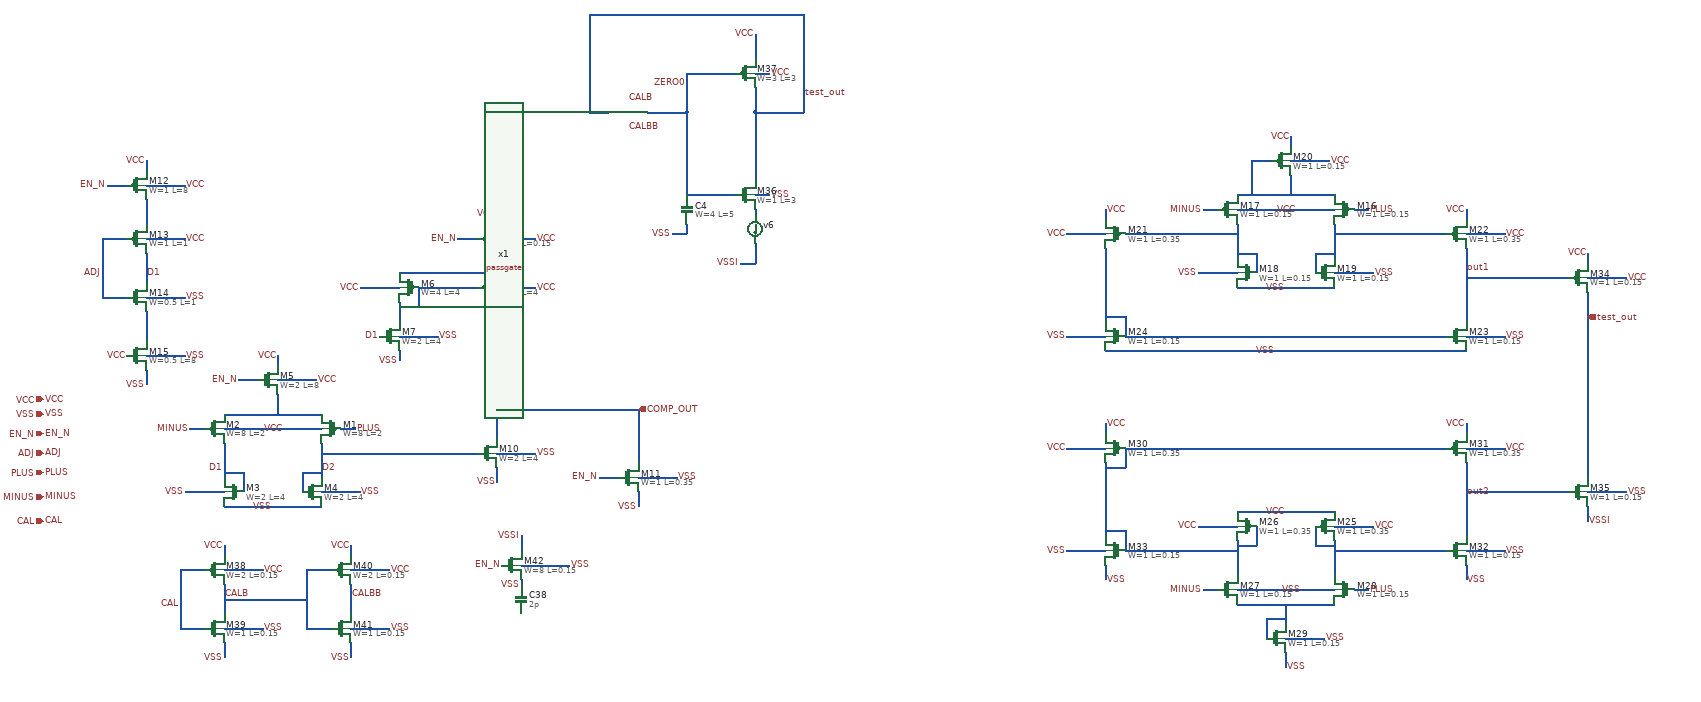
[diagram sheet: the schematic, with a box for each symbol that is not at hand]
v {xschem version=3.4.5 file_version=1.2
}
G {}
K {}
V {}
S {}
E {}
N 230 -90 230 -20 {
lab=D1}
N 430 -90 430 -20 {
lab=D2}
N 390 -30 390 10 {
lab=D2}
N 390 -30 430 -30 {
lab=D2}
N 270 -30 270 10 {
lab=D1}
N 230 -30 270 -30 {
lab=D1}
N 230 40 430 40 {
lab=VSS}
N 230 -150 430 -150 {
lab=#net1}
N 340 -190 340 -150 {
lab=#net1}
N 470 -120 500 -120 {
lab=PLUS}
N 160 -120 190 -120 {
lab=MINUS}
N 260 -220 300 -220 {
lab=EN_N}
N 590 -380 590 -340 {
lab=#net2}
N 340 -270 340 -250 {
lab=VCC}
N 340 -220 420 -220 {
lab=VCC}
N 230 -120 310 -120 {
lab=VCC}
N 310 -120 430 -120 {
lab=VCC}
N 430 10 510 10 {
lab=VSS}
N 150 10 230 10 {
lab=VSS}
N 590 -310 670 -310 {
lab=VSS}
N 630 -410 630 -370 {
lab=#net2}
N 590 -370 630 -370 {
lab=#net2}
N 630 -410 750 -410 {
lab=#net2}
N 790 -410 870 -410 {
lab=VCC}
N 510 -410 590 -410 {
lab=VCC}
N 590 -440 790 -440 {
lab=#net3}
N 790 -480 790 -440 {
lab=#net3}
N 710 -510 750 -510 {
lab=EN_N}
N 790 -510 870 -510 {
lab=VCC}
N 790 -560 790 -540 {
lab=VCC}
N 790 -380 790 -100 {
lab=COMP_OUT}
N 430 -70 750 -70 {
lab=D2}
N 790 -70 870 -70 {
lab=VSS}
N 790 -40 790 -10 {
lab=VSS}
N 1080 10 1080 40 {
lab=VSS}
N 1000 -20 1040 -20 {
lab=EN_N}
N 1080 -160 1080 -50 {
lab=COMP_OUT}
N 790 -160 1080 -160 {
lab=COMP_OUT}
N 70 -360 70 -300 {
lab=#net4}
N 70 -480 70 -420 {
lab=D1}
N 70 -590 70 -540 {
lab=#net5}
N 70 -670 70 -650 {
lab=VCC}
N -20 -510 30 -510 {
lab=ADJ}
N -20 -390 30 -390 {
lab=ADJ}
N -20 -510 -20 -390 {
lab=ADJ}
N 70 -240 70 -210 {
lab=VSS}
N 70 -510 150 -510 {
lab=VCC}
N 70 -620 150 -620 {
lab=VCC}
N 70 -270 150 -270 {
lab=VSS}
N 70 -390 150 -390 {
lab=VSS}
N -10 -620 30 -620 {
lab=EN_N}
N 2310 -540 2310 -470 {
lab=#net6}
N 2510 -540 2510 -470 {
lab=#net7}
N 2470 -480 2470 -440 {
lab=#net7}
N 2470 -480 2510 -480 {
lab=#net7}
N 2350 -480 2350 -440 {
lab=#net6}
N 2310 -480 2350 -480 {
lab=#net6}
N 2310 -410 2510 -410 {
lab=VSS}
N 2310 -600 2510 -600 {
lab=#net8}
N 2420 -640 2420 -600 {
lab=#net8}
N 2550 -570 2580 -570 {
lab=PLUS}
N 2240 -570 2270 -570 {
lab=MINUS}
N 2340 -670 2380 -670 {
lab=#net8}
N 2420 -720 2420 -700 {
lab=VCC}
N 2420 -670 2500 -670 {
lab=VCC}
N 2310 -570 2390 -570 {
lab=VCC}
N 2390 -570 2510 -570 {
lab=VCC}
N 2510 -440 2590 -440 {
lab=VSS}
N 2230 -440 2310 -440 {
lab=VSS}
N 2040 -490 2040 -340 {
lab=#net9}
N 2040 -570 2040 -550 {
lab=VCC}
N 1960 -520 2040 -520 {
lab=VCC}
N 2080 -520 2310 -520 {
lab=#net6}
N 2780 -570 2780 -550 {
lab=VCC}
N 2780 -520 2860 -520 {
lab=VCC}
N 2510 -520 2740 -520 {
lab=#net7}
N 2240 -280 2780 -280 {
lab=VSS}
N 2780 -310 2860 -310 {
lab=VSS}
N 2780 -490 2780 -340 {
lab=out1}
N 2040 -280 2240 -280 {
lab=VSS}
N 1960 -310 2040 -310 {
lab=VSS}
N 2080 -310 2740 -310 {
lab=#net9}
N 590 -280 590 -260 {
lab=VSS}
N 1080 -20 1160 -20 {
lab=VSS}
N 2080 -350 2080 -310 {
lab=#net9}
N 2040 -350 2080 -350 {
lab=#net9}
N 2340 -670 2340 -600 {
lab=#net8}
N 2310 110 2310 180 {
lab=#net10}
N 2510 110 2510 180 {
lab=#net11}
N 2310 240 2510 240 {
lab=#net12}
N 2550 210 2580 210 {
lab=PLUS}
N 2240 210 2270 210 {
lab=MINUS}
N 2040 -50 2040 100 {
lab=#net10}
N 2040 -130 2040 -110 {
lab=VCC}
N 1960 -80 2040 -80 {
lab=VCC}
N 2080 130 2310 130 {
lab=#net10}
N 2780 -130 2780 -110 {
lab=VCC}
N 2780 -80 2860 -80 {
lab=VCC}
N 2510 130 2740 130 {
lab=#net11}
N 2780 130 2860 130 {
lab=VSS}
N 2780 -50 2780 100 {
lab=out2}
N 1960 130 2040 130 {
lab=VSS}
N 2080 90 2080 130 {
lab=#net10}
N 2040 90 2080 90 {
lab=#net10}
N 2080 -80 2080 -40 {
lab=#net10}
N 2040 -40 2080 -40 {
lab=#net10}
N 2410 240 2410 280 {
lab=#net12}
N 2370 270 2370 310 {
lab=#net12}
N 2370 270 2410 270 {
lab=#net12}
N 2470 80 2470 120 {
lab=#net11}
N 2470 120 2510 120 {
lab=#net11}
N 2350 80 2350 120 {
lab=#net10}
N 2310 120 2350 120 {
lab=#net10}
N 2310 50 2510 50 {
lab=VCC}
N 2410 340 2410 370 {
lab=VSS}
N 2410 310 2490 310 {
lab=VSS}
N 2310 210 2510 210 {
lab=VSS}
N 2510 80 2590 80 {
lab=VCC}
N 2230 80 2310 80 {
lab=VCC}
N 2040 160 2040 190 {
lab=VSS}
N 2780 160 2780 190 {
lab=VSS}
N 2080 -80 2740 -80 {
lab=#net10}
N 3030 -480 3030 -460 {
lab=VCC}
N 3030 -430 3110 -430 {
lab=VCC}
N 2780 -430 2990 -430 {
lab=out1}
N 3030 -400 3030 -330 {
lab=test_out}
N 3030 10 3110 10 {
lab=VSS}
N 3030 40 3030 70 {
lab=VSS}
N 3030 -330 3030 -20 {
lab=test_out}
N 2780 10 2990 10 {
lab=out2}
N 1320 -600 1350 -600 {lab=VSS}
N 1320 -850 1350 -850 {lab=VCC}
N 1320 -930 1320 -880 {lab=VCC}
N 1290 -460 1320 -460 {lab=VSSI}
N 1320 -500 1320 -460 {lab=VSSI}
N 1180 -600 1280 -600 {lab=ZERO0}
N 1180 -770 1180 -600 {lab=ZERO0}
N 1100 -770 1180 -770 {lab=ZERO0}
N 980 -770 1020 -770 {lab=test_out}
N 980 -970 980 -770 {lab=test_out}
N 980 -970 1420 -970 {lab=test_out}
N 1320 -770 1420 -770 {lab=test_out}
N 1420 -970 1420 -770 {lab=test_out}
N 1320 -820 1320 -770 {lab=test_out}
N 1180 -850 1180 -770 {lab=ZERO0}
N 1320 -770 1320 -630 {lab=test_out}
N 1180 -850 1280 -850 {lab=ZERO0}
N 1150 -520 1180 -520 {lab=VSS}
N 1180 -540 1180 -520 { lab=VSS}
N 1320 -570 1320 -560 { lab=#net13}
N 230 200 230 260 {
lab=CALB}
N 140 170 190 170 {
lab=CAL}
N 140 290 190 290 {
lab=CAL}
N 140 170 140 290 {
lab=CAL}
N 230 170 310 170 {
lab=VCC}
N 230 290 310 290 {
lab=VSS}
N 230 320 230 350 {
lab=VSS}
N 490 200 490 260 {
lab=CALBB}
N 400 170 450 170 {
lab=CALB}
N 400 290 450 290 {
lab=CALB}
N 400 170 400 290 {
lab=CALB}
N 490 170 570 170 {
lab=VCC}
N 490 290 570 290 {
lab=VSS}
N 490 320 490 350 {
lab=VSS}
N 230 230 400 230 {
lab=CALB}
N 230 120 230 140 {
lab=VCC}
N 490 120 490 140 {
lab=VCC}
N 840 160 940 160 {lab=VSS}
N 840 100 840 130 {lab=VSSI}
N 840 190 840 220 {lab=VSS}
C {sky130_fd_pr/pfet_01v8.sym} 450 -120 0 1 {name=M1
L=2
W=8
nf=1
mult=1
ad="'int((nf+1)/2) * W/nf * 0.29'" 
pd="'2*int((nf+1)/2) * (W/nf + 0.29)'"
as="'int((nf+2)/2) * W/nf * 0.29'" 
ps="'2*int((nf+2)/2) * (W/nf + 0.29)'"
nrd="'0.29 / W'" nrs="'0.29 / W'"
sa=0 sb=0 sd=0
model=pfet_01v8
spiceprefix=X
}
C {sky130_fd_pr/pfet_01v8.sym} 210 -120 0 0 {name=M2
L=2
W=8
nf=1
mult=1
ad="'int((nf+1)/2) * W/nf * 0.29'" 
pd="'2*int((nf+1)/2) * (W/nf + 0.29)'"
as="'int((nf+2)/2) * W/nf * 0.29'" 
ps="'2*int((nf+2)/2) * (W/nf + 0.29)'"
nrd="'0.29 / W'" nrs="'0.29 / W'"
sa=0 sb=0 sd=0
model=pfet_01v8
spiceprefix=X
}
C {sky130_fd_pr/nfet_01v8_lvt.sym} 250 10 0 1 {name=M3
L=4
W=2
nf=1
mult=1
ad="'int((nf+1)/2) * W/nf * 0.29'" 
pd="'2*int((nf+1)/2) * (W/nf + 0.29)'"
as="'int((nf+2)/2) * W/nf * 0.29'" 
ps="'2*int((nf+2)/2) * (W/nf + 0.29)'"
nrd="'0.29 / W'" nrs="'0.29 / W'"
sa=0 sb=0 sd=0
model=nfet_01v8_lvt
spiceprefix=X
}
C {sky130_fd_pr/nfet_01v8_lvt.sym} 410 10 0 0 {name=M4
L=4
W=2
nf=1
mult=1
ad="'int((nf+1)/2) * W/nf * 0.29'" 
pd="'2*int((nf+1)/2) * (W/nf + 0.29)'"
as="'int((nf+2)/2) * W/nf * 0.29'" 
ps="'2*int((nf+2)/2) * (W/nf + 0.29)'"
nrd="'0.29 / W'" nrs="'0.29 / W'"
sa=0 sb=0 sd=0
model=nfet_01v8_lvt
spiceprefix=X
}
C {sky130_fd_pr/pfet_01v8.sym} 320 -220 0 0 {name=M5
L=8
W=2
nf=1
mult=1
ad="'int((nf+1)/2) * W/nf * 0.29'" 
pd="'2*int((nf+1)/2) * (W/nf + 0.29)'"
as="'int((nf+2)/2) * W/nf * 0.29'" 
ps="'2*int((nf+2)/2) * (W/nf + 0.29)'"
nrd="'0.29 / W'" nrs="'0.29 / W'"
sa=0 sb=0 sd=0
model=pfet_01v8
spiceprefix=X
}
C {sky130_fd_pr/pfet_01v8_lvt.sym} 610 -410 0 1 {name=M6
L=4
W=4
nf=1
mult=1
ad="'int((nf+1)/2) * W/nf * 0.29'" 
pd="'2*int((nf+1)/2) * (W/nf + 0.29)'"
as="'int((nf+2)/2) * W/nf * 0.29'" 
ps="'2*int((nf+2)/2) * (W/nf + 0.29)'"
nrd="'0.29 / W'" nrs="'0.29 / W'"
sa=0 sb=0 sd=0
model=pfet_01v8_lvt
spiceprefix=X
}
C {sky130_fd_pr/nfet_01v8_lvt.sym} 570 -310 0 0 {name=M7
L=4
W=2
nf=1
mult=1
ad="'int((nf+1)/2) * W/nf * 0.29'" 
pd="'2*int((nf+1)/2) * (W/nf + 0.29)'"
as="'int((nf+2)/2) * W/nf * 0.29'" 
ps="'2*int((nf+2)/2) * (W/nf + 0.29)'"
nrd="'0.29 / W'" nrs="'0.29 / W'"
sa=0 sb=0 sd=0
model=nfet_01v8_lvt
spiceprefix=X
}
C {devices/lab_wire.sym} 230 -40 0 0 {name=p1 sig_type=std_logic lab=D1}
C {devices/lab_wire.sym} 430 -40 0 1 {name=p2 sig_type=std_logic lab=D2}
C {devices/lab_wire.sym} 500 -120 0 1 {name=p3 sig_type=std_logic lab=PLUS}
C {devices/lab_wire.sym} 160 -120 0 0 {name=p4 sig_type=std_logic lab=MINUS}
C {devices/lab_wire.sym} 260 -220 0 0 {name=p5 sig_type=std_logic lab=EN_N}
C {devices/lab_wire.sym} 340 -270 0 0 {name=p6 sig_type=std_logic lab=VCC}
C {devices/lab_wire.sym} 420 -220 0 1 {name=p7 sig_type=std_logic lab=VCC}
C {devices/lab_wire.sym} 310 -120 0 1 {name=p8 sig_type=std_logic lab=VCC}
C {devices/lab_wire.sym} 510 10 0 1 {name=p9 sig_type=std_logic lab=VSS}
C {devices/lab_wire.sym} 150 10 0 0 {name=p10 sig_type=std_logic lab=VSS}
C {devices/lab_wire.sym} 670 -310 0 1 {name=p11 sig_type=std_logic lab=VSS}
C {devices/lab_wire.sym} 550 -310 0 0 {name=p12 sig_type=std_logic lab=D1}
C {sky130_fd_pr/pfet_01v8_lvt.sym} 770 -410 0 0 {name=M8
L=4
W=4
nf=1
mult=1
ad="'int((nf+1)/2) * W/nf * 0.29'" 
pd="'2*int((nf+1)/2) * (W/nf + 0.29)'"
as="'int((nf+2)/2) * W/nf * 0.29'" 
ps="'2*int((nf+2)/2) * (W/nf + 0.29)'"
nrd="'0.29 / W'" nrs="'0.29 / W'"
sa=0 sb=0 sd=0
model=pfet_01v8_lvt
spiceprefix=X
}
C {devices/lab_wire.sym} 870 -410 0 1 {name=p13 sig_type=std_logic lab=VCC}
C {devices/lab_wire.sym} 510 -410 0 0 {name=p14 sig_type=std_logic lab=VCC}
C {sky130_fd_pr/pfet_01v8.sym} 770 -510 0 0 {name=M9
L=0.15
W=5
nf=1
mult=1
ad="'int((nf+1)/2) * W/nf * 0.29'" 
pd="'2*int((nf+1)/2) * (W/nf + 0.29)'"
as="'int((nf+2)/2) * W/nf * 0.29'" 
ps="'2*int((nf+2)/2) * (W/nf + 0.29)'"
nrd="'0.29 / W'" nrs="'0.29 / W'"
sa=0 sb=0 sd=0
model=pfet_01v8
spiceprefix=X
}
C {devices/lab_wire.sym} 710 -510 0 0 {name=p15 sig_type=std_logic lab=EN_N}
C {devices/lab_wire.sym} 870 -510 0 1 {name=p16 sig_type=std_logic lab=VCC}
C {devices/lab_wire.sym} 790 -560 0 0 {name=p17 sig_type=std_logic lab=VCC}
C {devices/lab_wire.sym} 330 40 0 0 {name=p18 sig_type=std_logic lab=VSS}
C {sky130_fd_pr/nfet_01v8_lvt.sym} 770 -70 0 0 {name=M10
L=4
W=2
nf=1
mult=1
ad="'int((nf+1)/2) * W/nf * 0.29'" 
pd="'2*int((nf+1)/2) * (W/nf + 0.29)'"
as="'int((nf+2)/2) * W/nf * 0.29'" 
ps="'2*int((nf+2)/2) * (W/nf + 0.29)'"
nrd="'0.29 / W'" nrs="'0.29 / W'"
sa=0 sb=0 sd=0
model=nfet_01v8_lvt
spiceprefix=X
}
C {devices/lab_wire.sym} 870 -70 0 1 {name=p19 sig_type=std_logic lab=VSS}
C {devices/lab_wire.sym} 790 -10 0 0 {name=p20 sig_type=std_logic lab=VSS}
C {sky130_fd_pr/nfet_01v8.sym} 1060 -20 0 0 {name=M11
L=0.35
W=1
nf=1
mult=1
ad="'int((nf+1)/2) * W/nf * 0.29'" 
pd="'2*int((nf+1)/2) * (W/nf + 0.29)'"
as="'int((nf+2)/2) * W/nf * 0.29'" 
ps="'2*int((nf+2)/2) * (W/nf + 0.29)'"
nrd="'0.29 / W'" nrs="'0.29 / W'"
sa=0 sb=0 sd=0
model=nfet_01v8
spiceprefix=X
}
C {devices/lab_wire.sym} 1080 40 0 0 {name=p21 sig_type=std_logic lab=VSS}
C {devices/lab_wire.sym} 1000 -20 0 0 {name=p22 sig_type=std_logic lab=EN_N}
C {sky130_fd_pr/pfet_01v8.sym} 50 -620 0 0 {name=M12
L=8
W=1
nf=1
mult=1
ad="'int((nf+1)/2) * W/nf * 0.29'" 
pd="'2*int((nf+1)/2) * (W/nf + 0.29)'"
as="'int((nf+2)/2) * W/nf * 0.29'" 
ps="'2*int((nf+2)/2) * (W/nf + 0.29)'"
nrd="'0.29 / W'" nrs="'0.29 / W'"
sa=0 sb=0 sd=0
model=pfet_01v8
spiceprefix=X
}
C {sky130_fd_pr/pfet_01v8_lvt.sym} 50 -510 0 0 {name=M13
L=1
W=1
nf=1
mult=1
ad="'int((nf+1)/2) * W/nf * 0.29'" 
pd="'2*int((nf+1)/2) * (W/nf + 0.29)'"
as="'int((nf+2)/2) * W/nf * 0.29'" 
ps="'2*int((nf+2)/2) * (W/nf + 0.29)'"
nrd="'0.29 / W'" nrs="'0.29 / W'"
sa=0 sb=0 sd=0
model=pfet_01v8_lvt
spiceprefix=X
}
C {sky130_fd_pr/nfet_01v8_lvt.sym} 50 -390 0 0 {name=M14
L=1
W=0.5
nf=1
mult=1
ad="'int((nf+1)/2) * W/nf * 0.29'" 
pd="'2*int((nf+1)/2) * (W/nf + 0.29)'"
as="'int((nf+2)/2) * W/nf * 0.29'" 
ps="'2*int((nf+2)/2) * (W/nf + 0.29)'"
nrd="'0.29 / W'" nrs="'0.29 / W'"
sa=0 sb=0 sd=0
model=nfet_01v8_lvt
spiceprefix=X
}
C {sky130_fd_pr/nfet_01v8_lvt.sym} 50 -270 0 0 {name=M15
L=8
W=0.5
nf=1
mult=1
ad="'int((nf+1)/2) * W/nf * 0.29'" 
pd="'2*int((nf+1)/2) * (W/nf + 0.29)'"
as="'int((nf+2)/2) * W/nf * 0.29'" 
ps="'2*int((nf+2)/2) * (W/nf + 0.29)'"
nrd="'0.29 / W'" nrs="'0.29 / W'"
sa=0 sb=0 sd=0
model=nfet_01v8_lvt
spiceprefix=X
}
C {devices/lab_wire.sym} 70 -670 0 0 {name=p23 sig_type=std_logic lab=VCC}
C {devices/lab_wire.sym} 70 -440 0 1 {name=p24 sig_type=std_logic lab=D1}
C {devices/lab_wire.sym} -20 -440 0 0 {name=p25 sig_type=std_logic lab=ADJ}
C {devices/lab_wire.sym} 70 -210 0 0 {name=p26 sig_type=std_logic lab=VSS}
C {devices/lab_wire.sym} 150 -510 0 1 {name=p27 sig_type=std_logic lab=VCC}
C {devices/lab_wire.sym} 150 -620 0 1 {name=p28 sig_type=std_logic lab=VCC}
C {devices/lab_wire.sym} 150 -270 0 1 {name=p29 sig_type=std_logic lab=VSS}
C {devices/lab_wire.sym} 150 -390 0 1 {name=p30 sig_type=std_logic lab=VSS}
C {devices/lab_wire.sym} 30 -270 0 0 {name=p31 sig_type=std_logic lab=VCC}
C {devices/lab_wire.sym} -10 -620 0 0 {name=p32 sig_type=std_logic lab=EN_N}
C {devices/ipin.sym} -140 -180 0 0 {name=p33 lab=VCC}
C {devices/ipin.sym} -140 -150 0 0 {name=p34 lab=VSS}
C {devices/ipin.sym} -140 -110 0 0 {name=p35 lab=EN_N}
C {devices/ipin.sym} -140 -70 0 0 {name=p36 lab=ADJ}
C {devices/ipin.sym} -140 -30 0 0 {name=p37 lab=PLUS}
C {devices/ipin.sym} -140 20 0 0 {name=p38 lab=MINUS}
C {devices/opin.sym} 1080 -160 0 0 {name=p39 lab=COMP_OUT}
C {sky130_fd_pr/pfet_01v8.sym} 2530 -570 0 1 {name=M16
L=0.15
W=1
nf=1
mult=1
ad="'int((nf+1)/2) * W/nf * 0.29'" 
pd="'2*int((nf+1)/2) * (W/nf + 0.29)'"
as="'int((nf+2)/2) * W/nf * 0.29'" 
ps="'2*int((nf+2)/2) * (W/nf + 0.29)'"
nrd="'0.29 / W'" nrs="'0.29 / W'"
sa=0 sb=0 sd=0
model=pfet_01v8
spiceprefix=X
}
C {sky130_fd_pr/pfet_01v8.sym} 2290 -570 0 0 {name=M17
L=0.15
W=1
nf=1
mult=1
ad="'int((nf+1)/2) * W/nf * 0.29'" 
pd="'2*int((nf+1)/2) * (W/nf + 0.29)'"
as="'int((nf+2)/2) * W/nf * 0.29'" 
ps="'2*int((nf+2)/2) * (W/nf + 0.29)'"
nrd="'0.29 / W'" nrs="'0.29 / W'"
sa=0 sb=0 sd=0
model=pfet_01v8
spiceprefix=X
}
C {sky130_fd_pr/nfet_01v8_lvt.sym} 2330 -440 0 1 {name=M18
L=0.15
W=1
nf=1
mult=1
ad="'int((nf+1)/2) * W/nf * 0.29'" 
pd="'2*int((nf+1)/2) * (W/nf + 0.29)'"
as="'int((nf+2)/2) * W/nf * 0.29'" 
ps="'2*int((nf+2)/2) * (W/nf + 0.29)'"
nrd="'0.29 / W'" nrs="'0.29 / W'"
sa=0 sb=0 sd=0
model=nfet_01v8_lvt
spiceprefix=X
}
C {sky130_fd_pr/nfet_01v8_lvt.sym} 2490 -440 0 0 {name=M19
L=0.15
W=1
nf=1
mult=1
ad="'int((nf+1)/2) * W/nf * 0.29'" 
pd="'2*int((nf+1)/2) * (W/nf + 0.29)'"
as="'int((nf+2)/2) * W/nf * 0.29'" 
ps="'2*int((nf+2)/2) * (W/nf + 0.29)'"
nrd="'0.29 / W'" nrs="'0.29 / W'"
sa=0 sb=0 sd=0
model=nfet_01v8_lvt
spiceprefix=X
}
C {sky130_fd_pr/pfet_01v8.sym} 2400 -670 0 0 {name=M20
L=0.15
W=1
nf=1
mult=1
ad="'int((nf+1)/2) * W/nf * 0.29'" 
pd="'2*int((nf+1)/2) * (W/nf + 0.29)'"
as="'int((nf+2)/2) * W/nf * 0.29'" 
ps="'2*int((nf+2)/2) * (W/nf + 0.29)'"
nrd="'0.29 / W'" nrs="'0.29 / W'"
sa=0 sb=0 sd=0
model=pfet_01v8
spiceprefix=X
}
C {devices/lab_wire.sym} 2580 -570 0 1 {name=p42 sig_type=std_logic lab=PLUS}
C {devices/lab_wire.sym} 2240 -570 0 0 {name=p43 sig_type=std_logic lab=MINUS}
C {devices/lab_wire.sym} 2420 -720 0 0 {name=p45 sig_type=std_logic lab=VCC}
C {devices/lab_wire.sym} 2500 -670 0 1 {name=p46 sig_type=std_logic lab=VCC}
C {devices/lab_wire.sym} 2390 -570 0 1 {name=p47 sig_type=std_logic lab=VCC}
C {devices/lab_wire.sym} 2590 -440 0 1 {name=p48 sig_type=std_logic lab=VSS}
C {devices/lab_wire.sym} 2230 -440 0 0 {name=p49 sig_type=std_logic lab=VSS}
C {devices/lab_wire.sym} 2410 -410 0 0 {name=p50 sig_type=std_logic lab=VSS}
C {sky130_fd_pr/pfet_01v8_lvt.sym} 2060 -520 0 1 {name=M21
L=0.35
W=1
nf=1
mult=1
ad="'int((nf+1)/2) * W/nf * 0.29'" 
pd="'2*int((nf+1)/2) * (W/nf + 0.29)'"
as="'int((nf+2)/2) * W/nf * 0.29'" 
ps="'2*int((nf+2)/2) * (W/nf + 0.29)'"
nrd="'0.29 / W'" nrs="'0.29 / W'"
sa=0 sb=0 sd=0
model=pfet_01v8_lvt
spiceprefix=X
}
C {devices/lab_wire.sym} 2040 -570 0 1 {name=p52 sig_type=std_logic lab=VCC}
C {devices/lab_wire.sym} 1960 -520 0 0 {name=p53 sig_type=std_logic lab=VCC}
C {sky130_fd_pr/pfet_01v8_lvt.sym} 2760 -520 0 0 {name=M22
L=0.35
W=1
nf=1
mult=1
ad="'int((nf+1)/2) * W/nf * 0.29'" 
pd="'2*int((nf+1)/2) * (W/nf + 0.29)'"
as="'int((nf+2)/2) * W/nf * 0.29'" 
ps="'2*int((nf+2)/2) * (W/nf + 0.29)'"
nrd="'0.29 / W'" nrs="'0.29 / W'"
sa=0 sb=0 sd=0
model=pfet_01v8_lvt
spiceprefix=X
}
C {devices/lab_wire.sym} 2780 -570 0 0 {name=p51 sig_type=std_logic lab=VCC}
C {devices/lab_wire.sym} 2860 -520 0 1 {name=p54 sig_type=std_logic lab=VCC}
C {sky130_fd_pr/nfet_01v8_lvt.sym} 2760 -310 0 0 {name=M23
L=0.15
W=1
nf=1
mult=1
ad="'int((nf+1)/2) * W/nf * 0.29'" 
pd="'2*int((nf+1)/2) * (W/nf + 0.29)'"
as="'int((nf+2)/2) * W/nf * 0.29'" 
ps="'2*int((nf+2)/2) * (W/nf + 0.29)'"
nrd="'0.29 / W'" nrs="'0.29 / W'"
sa=0 sb=0 sd=0
model=nfet_01v8_lvt
spiceprefix=X
}
C {devices/lab_wire.sym} 2860 -310 0 1 {name=p55 sig_type=std_logic lab=VSS}
C {sky130_fd_pr/nfet_01v8_lvt.sym} 2060 -310 0 1 {name=M24
L=0.15
W=1
nf=1
mult=1
ad="'int((nf+1)/2) * W/nf * 0.29'" 
pd="'2*int((nf+1)/2) * (W/nf + 0.29)'"
as="'int((nf+2)/2) * W/nf * 0.29'" 
ps="'2*int((nf+2)/2) * (W/nf + 0.29)'"
nrd="'0.29 / W'" nrs="'0.29 / W'"
sa=0 sb=0 sd=0
model=nfet_01v8_lvt
spiceprefix=X
}
C {devices/lab_wire.sym} 1960 -310 0 0 {name=p57 sig_type=std_logic lab=VSS}
C {devices/lab_wire.sym} 2390 -280 0 0 {name=p58 sig_type=std_logic lab=VSS}
C {devices/lab_wire.sym} 590 -260 0 0 {name=p59 sig_type=std_logic lab=VSS}
C {devices/lab_wire.sym} -140 -180 0 1 {name=p40 sig_type=std_logic lab=VCC}
C {devices/lab_wire.sym} -140 -150 0 1 {name=p41 sig_type=std_logic lab=VSS}
C {devices/lab_wire.sym} -140 -70 0 1 {name=p60 sig_type=std_logic lab=ADJ}
C {devices/lab_wire.sym} -140 20 0 1 {name=p61 sig_type=std_logic lab=MINUS}
C {devices/lab_wire.sym} -140 -30 0 1 {name=p62 sig_type=std_logic lab=PLUS}
C {devices/lab_wire.sym} -140 -110 0 1 {name=p63 sig_type=std_logic lab=EN_N}
C {devices/lab_wire.sym} 1160 -20 0 1 {name=p64 sig_type=std_logic lab=VSS}
C {devices/opin.sym} 3030 -350 0 0 {name=p65 lab=test_out}
C {sky130_fd_pr/nfet_01v8.sym} 2290 210 0 0 {name=M27
L=0.15
W=1
nf=1
mult=1
ad="'int((nf+1)/2) * W/nf * 0.29'" 
pd="'2*int((nf+1)/2) * (W/nf + 0.29)'"
as="'int((nf+2)/2) * W/nf * 0.29'" 
ps="'2*int((nf+2)/2) * (W/nf + 0.29)'"
nrd="'0.29 / W'" nrs="'0.29 / W'"
sa=0 sb=0 sd=0
model=nfet_01v8
spiceprefix=X
}
C {sky130_fd_pr/nfet_01v8.sym} 2530 210 0 1 {name=M28
L=0.15
W=1
nf=1
mult=1
ad="'int((nf+1)/2) * W/nf * 0.29'" 
pd="'2*int((nf+1)/2) * (W/nf + 0.29)'"
as="'int((nf+2)/2) * W/nf * 0.29'" 
ps="'2*int((nf+2)/2) * (W/nf + 0.29)'"
nrd="'0.29 / W'" nrs="'0.29 / W'"
sa=0 sb=0 sd=0
model=nfet_01v8
spiceprefix=X
}
C {devices/lab_wire.sym} 2580 210 0 1 {name=p44 sig_type=std_logic lab=PLUS}
C {devices/lab_wire.sym} 2240 210 0 0 {name=p56 sig_type=std_logic lab=MINUS}
C {sky130_fd_pr/pfet_01v8_lvt.sym} 2060 -80 0 1 {name=M30
L=0.35
W=1
nf=1
mult=1
ad="'int((nf+1)/2) * W/nf * 0.29'" 
pd="'2*int((nf+1)/2) * (W/nf + 0.29)'"
as="'int((nf+2)/2) * W/nf * 0.29'" 
ps="'2*int((nf+2)/2) * (W/nf + 0.29)'"
nrd="'0.29 / W'" nrs="'0.29 / W'"
sa=0 sb=0 sd=0
model=pfet_01v8_lvt
spiceprefix=X
}
C {devices/lab_wire.sym} 2040 -130 0 1 {name=p72 sig_type=std_logic lab=VCC}
C {sky130_fd_pr/pfet_01v8_lvt.sym} 2760 -80 0 0 {name=M31
L=0.35
W=1
nf=1
mult=1
ad="'int((nf+1)/2) * W/nf * 0.29'" 
pd="'2*int((nf+1)/2) * (W/nf + 0.29)'"
as="'int((nf+2)/2) * W/nf * 0.29'" 
ps="'2*int((nf+2)/2) * (W/nf + 0.29)'"
nrd="'0.29 / W'" nrs="'0.29 / W'"
sa=0 sb=0 sd=0
model=pfet_01v8_lvt
spiceprefix=X
}
C {devices/lab_wire.sym} 2780 -130 0 0 {name=p74 sig_type=std_logic lab=VCC}
C {devices/lab_wire.sym} 2860 -80 0 1 {name=p75 sig_type=std_logic lab=VCC}
C {sky130_fd_pr/nfet_01v8_lvt.sym} 2760 130 0 0 {name=M32
L=0.15
W=1
nf=1
mult=1
ad="'int((nf+1)/2) * W/nf * 0.29'" 
pd="'2*int((nf+1)/2) * (W/nf + 0.29)'"
as="'int((nf+2)/2) * W/nf * 0.29'" 
ps="'2*int((nf+2)/2) * (W/nf + 0.29)'"
nrd="'0.29 / W'" nrs="'0.29 / W'"
sa=0 sb=0 sd=0
model=nfet_01v8_lvt
spiceprefix=X
}
C {devices/lab_wire.sym} 2860 130 0 1 {name=p76 sig_type=std_logic lab=VSS}
C {sky130_fd_pr/nfet_01v8_lvt.sym} 2060 130 0 1 {name=M33
L=0.15
W=1
nf=1
mult=1
ad="'int((nf+1)/2) * W/nf * 0.29'" 
pd="'2*int((nf+1)/2) * (W/nf + 0.29)'"
as="'int((nf+2)/2) * W/nf * 0.29'" 
ps="'2*int((nf+2)/2) * (W/nf + 0.29)'"
nrd="'0.29 / W'" nrs="'0.29 / W'"
sa=0 sb=0 sd=0
model=nfet_01v8_lvt
spiceprefix=X
}
C {sky130_fd_pr/nfet_01v8.sym} 2390 310 0 0 {name=M29
L=0.15
W=1
nf=1
mult=1
ad="'int((nf+1)/2) * W/nf * 0.29'" 
pd="'2*int((nf+1)/2) * (W/nf + 0.29)'"
as="'int((nf+2)/2) * W/nf * 0.29'" 
ps="'2*int((nf+2)/2) * (W/nf + 0.29)'"
nrd="'0.29 / W'" nrs="'0.29 / W'"
sa=0 sb=0 sd=0
model=nfet_01v8
spiceprefix=X
}
C {devices/lab_wire.sym} 2410 50 0 0 {name=p66 sig_type=std_logic lab=VCC}
C {devices/lab_wire.sym} 2410 370 0 1 {name=p67 sig_type=std_logic lab=VSS}
C {devices/lab_wire.sym} 2490 310 0 1 {name=p68 sig_type=std_logic lab=VSS}
C {devices/lab_wire.sym} 2400 210 0 1 {name=p69 sig_type=std_logic lab=VSS}
C {devices/lab_wire.sym} 2590 80 0 1 {name=p70 sig_type=std_logic lab=VCC}
C {devices/lab_wire.sym} 2230 80 0 0 {name=p71 sig_type=std_logic lab=VCC}
C {devices/lab_wire.sym} 2040 190 0 1 {name=p78 sig_type=std_logic lab=VSS}
C {devices/lab_wire.sym} 2780 190 0 1 {name=p80 sig_type=std_logic lab=VSS}
C {devices/lab_wire.sym} 2780 10 0 1 {name=p79 sig_type=std_logic lab=out2}
C {sky130_fd_pr/pfet_01v8.sym} 3010 -430 0 0 {name=M34
L=0.15
W=1
nf=1
mult=1
ad="'int((nf+1)/2) * W/nf * 0.29'" 
pd="'2*int((nf+1)/2) * (W/nf + 0.29)'"
as="'int((nf+2)/2) * W/nf * 0.29'" 
ps="'2*int((nf+2)/2) * (W/nf + 0.29)'"
nrd="'0.29 / W'" nrs="'0.29 / W'"
sa=0 sb=0 sd=0
model=pfet_01v8
spiceprefix=X
}
C {devices/lab_wire.sym} 3030 -480 0 0 {name=p81 sig_type=std_logic lab=VCC}
C {devices/lab_wire.sym} 3110 -430 0 1 {name=p82 sig_type=std_logic lab=VCC}
C {devices/lab_wire.sym} 2780 -450 0 1 {name=p83 sig_type=std_logic lab=out1}
C {sky130_fd_pr/nfet_01v8.sym} 3010 10 0 0 {name=M35
L=0.15
W=1
nf=1
mult=1
ad="'int((nf+1)/2) * W/nf * 0.29'" 
pd="'2*int((nf+1)/2) * (W/nf + 0.29)'"
as="'int((nf+2)/2) * W/nf * 0.29'" 
ps="'2*int((nf+2)/2) * (W/nf + 0.29)'"
nrd="'0.29 / W'" nrs="'0.29 / W'"
sa=0 sb=0 sd=0
model=nfet_01v8
spiceprefix=X
}
C {devices/lab_wire.sym} 3110 10 0 1 {name=p84 sig_type=std_logic lab=VSS}
C {devices/lab_wire.sym} 3030 70 0 1 {name=p85 sig_type=std_logic lab=VSSI}
C {devices/lab_wire.sym} 1960 -80 0 0 {name=p73 sig_type=std_logic lab=VCC}
C {devices/lab_wire.sym} 1960 130 0 0 {name=p77 sig_type=std_logic lab=VSS}
C {sky130_fd_pr/pfet_01v8_lvt.sym} 2490 80 0 0 {name=M25
L=0.35
W=1
nf=1
mult=1
ad="'int((nf+1)/2) * W/nf * 0.29'" 
pd="'2*int((nf+1)/2) * (W/nf + 0.29)'"
as="'int((nf+2)/2) * W/nf * 0.29'" 
ps="'2*int((nf+2)/2) * (W/nf + 0.29)'"
nrd="'0.29 / W'" nrs="'0.29 / W'"
sa=0 sb=0 sd=0
model=pfet_01v8_lvt
spiceprefix=X
}
C {sky130_fd_pr/pfet_01v8_lvt.sym} 2330 80 0 1 {name=M26
L=0.35
W=1
nf=1
mult=1
ad="'int((nf+1)/2) * W/nf * 0.29'" 
pd="'2*int((nf+1)/2) * (W/nf + 0.29)'"
as="'int((nf+2)/2) * W/nf * 0.29'" 
ps="'2*int((nf+2)/2) * (W/nf + 0.29)'"
nrd="'0.29 / W'" nrs="'0.29 / W'"
sa=0 sb=0 sd=0
model=pfet_01v8_lvt
spiceprefix=X
}
C {devices/lab_pin.sym} 1060 -800 0 1 {name=l19 sig_type=std_logic lab=CALB}
C {devices/lab_pin.sym} 1060 -740 0 1 {name=l44 sig_type=std_logic lab=CALBB}
C {devices/lab_pin.sym} 1350 -600 0 1 {name=p179 lab=VSS}
C {devices/lab_pin.sym} 1350 -850 0 1 {name=p180 lab=VCC}
C {devices/lab_pin.sym} 1320 -930 0 0 {name=p181 lab=VCC}
C {devices/lab_pin.sym} 1290 -460 0 0 {name=p182 lab=VSSI}
C {devices/lab_pin.sym} 1180 -830 0 0 {name=l48 lab=ZERO0}
C {devices/ammeter.sym} 1320 -530 0 0 {name=v6
current=4.2035e-06}
C {sky130_tests/passgate.sym} 1060 -770 0 1 {name=x1 m=1
W_N=0.42 L_N=0.15
W_P=0.7 L_P=0.15
VCCBPIN=VCC VSSBPIN=VSS}
C {devices/lab_pin.sym} 1150 -520 0 0 {name=p86 lab=VSS}
C {sky130_fd_pr/cap_mim_m3_1.sym} 1180 -570 0 0 {name=C4 model=cap_mim_m3_1 W=4 L=5 MF=1 spiceprefix=X}
C {sky130_fd_pr/nfet_01v8_lvt.sym} 1300 -600 0 0 {name=M36
L=3
W=1
ad="'W * 0.29'" pd="'2*(W + 0.29)'"
as="'W * 0.29'" ps="'2*(W + 0.29)'"
nrd=0 nrs=0
sa=0 sb=0 sd=0
nf=1 mult=1
model=nfet_01v8_lvt
spiceprefix=X
 }
C {sky130_fd_pr/pfet_01v8_lvt.sym} 1300 -850 0 0 {name=M37
L=3
W=3
ad="'W * 0.29'" pd="'2*(W + 0.29)'"
as="'W * 0.29'" ps="'2*(W + 0.29)'"
nrd=0 nrs=0
sa=0 sb=0 sd=0
nf=1 mult=1
model=pfet_01v8_lvt
spiceprefix=X
 }
C {devices/lab_wire.sym} 1420 -810 0 1 {name=p87 sig_type=std_logic lab=test_out}
C {devices/ipin.sym} -140 70 0 0 {name=p88 lab=CAL}
C {devices/lab_wire.sym} -140 70 0 1 {name=p89 sig_type=std_logic lab=CAL}
C {sky130_fd_pr/pfet_01v8.sym} 210 170 0 0 {name=M38
L=0.15
W=2
nf=1
mult=1
ad="'int((nf+1)/2) * W/nf * 0.29'" 
pd="'2*int((nf+1)/2) * (W/nf + 0.29)'"
as="'int((nf+2)/2) * W/nf * 0.29'" 
ps="'2*int((nf+2)/2) * (W/nf + 0.29)'"
nrd="'0.29 / W'" nrs="'0.29 / W'"
sa=0 sb=0 sd=0
model=pfet_01v8
spiceprefix=X
}
C {sky130_fd_pr/nfet_01v8.sym} 210 290 0 0 {name=M39
L=0.15
W=1
nf=1
mult=1
ad="'int((nf+1)/2) * W/nf * 0.29'" 
pd="'2*int((nf+1)/2) * (W/nf + 0.29)'"
as="'int((nf+2)/2) * W/nf * 0.29'" 
ps="'2*int((nf+2)/2) * (W/nf + 0.29)'"
nrd="'0.29 / W'" nrs="'0.29 / W'"
sa=0 sb=0 sd=0
model=nfet_01v8
spiceprefix=X
}
C {devices/lab_wire.sym} 230 220 0 1 {name=p90 sig_type=std_logic lab=CALB}
C {devices/lab_wire.sym} 140 240 0 0 {name=p91 sig_type=std_logic lab=CAL}
C {devices/lab_wire.sym} 310 170 0 1 {name=p92 sig_type=std_logic lab=VCC}
C {devices/lab_wire.sym} 310 290 0 1 {name=p93 sig_type=std_logic lab=VSS}
C {devices/lab_wire.sym} 230 350 0 0 {name=p94 sig_type=std_logic lab=VSS}
C {sky130_fd_pr/pfet_01v8.sym} 470 170 0 0 {name=M40
L=0.15
W=2
nf=1
mult=1
ad="'int((nf+1)/2) * W/nf * 0.29'" 
pd="'2*int((nf+1)/2) * (W/nf + 0.29)'"
as="'int((nf+2)/2) * W/nf * 0.29'" 
ps="'2*int((nf+2)/2) * (W/nf + 0.29)'"
nrd="'0.29 / W'" nrs="'0.29 / W'"
sa=0 sb=0 sd=0
model=pfet_01v8
spiceprefix=X
}
C {sky130_fd_pr/nfet_01v8.sym} 470 290 0 0 {name=M41
L=0.15
W=1
nf=1
mult=1
ad="'int((nf+1)/2) * W/nf * 0.29'" 
pd="'2*int((nf+1)/2) * (W/nf + 0.29)'"
as="'int((nf+2)/2) * W/nf * 0.29'" 
ps="'2*int((nf+2)/2) * (W/nf + 0.29)'"
nrd="'0.29 / W'" nrs="'0.29 / W'"
sa=0 sb=0 sd=0
model=nfet_01v8
spiceprefix=X
}
C {devices/lab_wire.sym} 490 220 0 1 {name=p95 sig_type=std_logic lab=CALBB}
C {devices/lab_wire.sym} 570 170 0 1 {name=p97 sig_type=std_logic lab=VCC}
C {devices/lab_wire.sym} 570 290 0 1 {name=p98 sig_type=std_logic lab=VSS}
C {devices/lab_wire.sym} 490 350 0 0 {name=p99 sig_type=std_logic lab=VSS}
C {devices/lab_wire.sym} 230 120 0 0 {name=p96 sig_type=std_logic lab=VCC}
C {devices/lab_wire.sym} 490 120 0 0 {name=p100 sig_type=std_logic lab=VCC}
C {devices/lab_pin.sym} 940 160 0 1 {name=p283 lab=VSS}
C {devices/lab_pin.sym} 800 160 0 0 {name=l56 lab=EN_N}
C {devices/lab_pin.sym} 840 200 0 0 {name=p284 lab=VSS}
C {devices/lab_pin.sym} 840 100 0 0 {name=p199 lab=VSSI}
C {devices/parax_cap.sym} 840 230 0 0 {name=C38  value=2p}
C {sky130_fd_pr/nfet_01v8.sym} 820 160 0 0 {name=M42
L=0.15
W=8
ad="'W * 0.29'" pd="'W + 2 * 0.29'"
as="'W * 0.29'" ps="'W + 2 * 0.29'"
nrd=0 nrs=0
sa=0 sb=0 sd=0
nf=1 mult=2
model=nfet_01v8
spiceprefix=X
 }
